One B-rep face of a CAD part: STEP entity #522.
In plain terms, the planar face has unit normal (1, 0, 0).
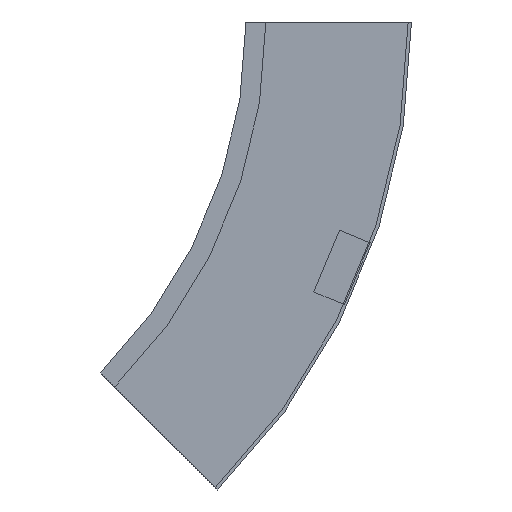
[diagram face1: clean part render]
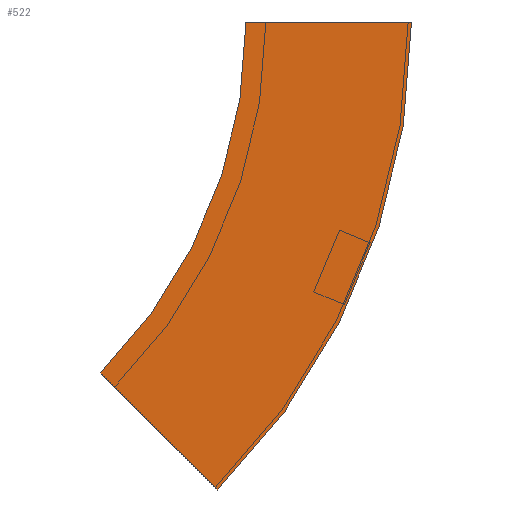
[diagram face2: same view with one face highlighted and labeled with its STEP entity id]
Its self-contained STEP definition (entity closure, numbers rounded to 3 decimals):
#2 = DIRECTION ( 'NONE',  ( 0., -1., 0. ) ) ;
#13 = DIRECTION ( 'NONE',  ( -1., 0., 0. ) ) ;
#21 = DIRECTION ( 'NONE',  ( 1., 0., 0. ) ) ;
#24 = VERTEX_POINT ( 'NONE', #482 ) ;
#41 = VECTOR ( 'NONE', #74, 1000. ) ;
#57 = PLANE ( 'NONE',  #373 ) ;
#62 = DIRECTION ( 'NONE',  ( 0., 0., 1. ) ) ;
#68 = ORIENTED_EDGE ( 'NONE', *, *, #517, .T. ) ;
#70 = EDGE_LOOP ( 'NONE', ( #405, #331, #68, #154 ) ) ;
#74 = DIRECTION ( 'NONE',  ( 0., 1., 0. ) ) ;
#109 = VERTEX_POINT ( 'NONE', #442 ) ;
#142 = DIRECTION ( 'NONE',  ( 0., -1., 0. ) ) ;
#150 = CIRCLE ( 'NONE', #278, 300. ) ;
#154 = ORIENTED_EDGE ( 'NONE', *, *, #320, .T. ) ;
#157 = FACE_OUTER_BOUND ( 'NONE', #70, .T. ) ;
#189 = CARTESIAN_POINT ( 'NONE',  ( 0., 300., 0. ) ) ;
#250 = LINE ( 'NONE', #299, #41 ) ;
#253 = CARTESIAN_POINT ( 'NONE',  ( 0., 300., 0. ) ) ;
#257 = DIRECTION ( 'NONE',  ( 1., 0., 0. ) ) ;
#278 = AXIS2_PLACEMENT_3D ( 'NONE', #189, #21, #142 ) ;
#295 = CARTESIAN_POINT ( 'NONE',  ( 0., -100., 0. ) ) ;
#299 = CARTESIAN_POINT ( 'NONE',  ( 0., -100., 0. ) ) ;
#304 = LINE ( 'NONE', #533, #360 ) ;
#310 = CARTESIAN_POINT ( 'NONE',  ( 0., 17.157, -282.843 ) ) ;
#311 = VERTEX_POINT ( 'NONE', #310 ) ;
#320 = EDGE_CURVE ( 'NONE', #311, #24, #304, .T. ) ;
#331 = ORIENTED_EDGE ( 'NONE', *, *, #508, .F. ) ;
#360 = VECTOR ( 'NONE', #485, 1000. ) ;
#373 = AXIS2_PLACEMENT_3D ( 'NONE', #400, #13, #62 ) ;
#389 = VERTEX_POINT ( 'NONE', #295 ) ;
#390 = AXIS2_PLACEMENT_3D ( 'NONE', #253, #257, #2 ) ;
#400 = CARTESIAN_POINT ( 'NONE',  ( 0., -100., 0. ) ) ;
#405 = ORIENTED_EDGE ( 'NONE', *, *, #564, .F. ) ;
#442 = CARTESIAN_POINT ( 'NONE',  ( 0., 0., 0. ) ) ;
#482 = CARTESIAN_POINT ( 'NONE',  ( 0., 87.868, -212.132 ) ) ;
#485 = DIRECTION ( 'NONE',  ( 0., 0.707, 0.707 ) ) ;
#508 = EDGE_CURVE ( 'NONE', #389, #109, #250, .T. ) ;
#517 = EDGE_CURVE ( 'NONE', #389, #311, #555, .T. ) ;
#522 = ADVANCED_FACE ( 'NONE', ( #157 ), #57, .F. ) ;
#533 = CARTESIAN_POINT ( 'NONE',  ( 0., 17.157, -282.843 ) ) ;
#555 = CIRCLE ( 'NONE', #390, 400. ) ;
#564 = EDGE_CURVE ( 'NONE', #109, #24, #150, .T. ) ;
